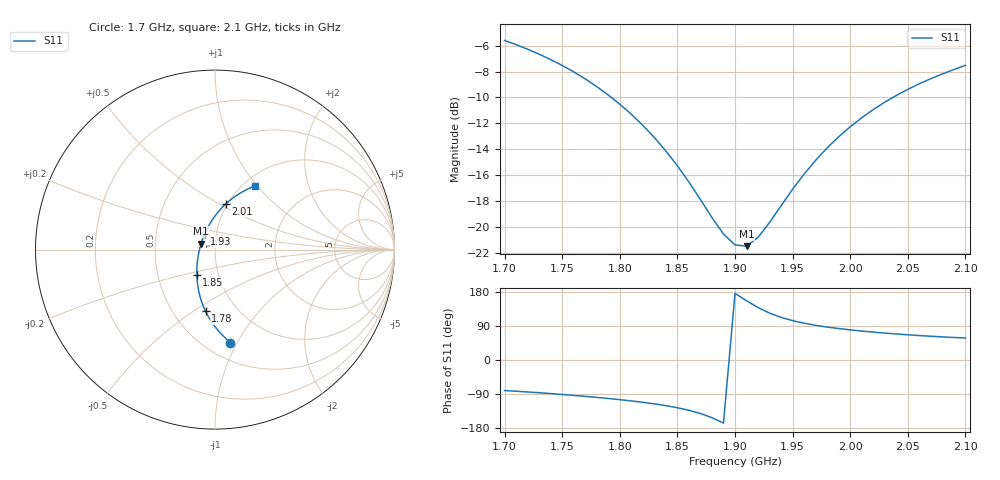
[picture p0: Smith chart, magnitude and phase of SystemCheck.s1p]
! Generated by circuitRF - EM: openEMS
! circuitRF-EM setup: SystemCheck Fine
! circuitRF-EM layout: SystemCheck.c3d
! circuitRF-EM written: 2026-10-19 01:18:16Z
! circuitRF-EM geometry: 3c7697fa9fd6841b
! circuitRF-EM mesh: 0e8366f4b078f3f9
! circuitRF-EM ports: 84820064c771a764
! circuitRF-EM model: openEMS 0.37.0 (v0.37.0, CSXCAD v0.7.0)
! circuitRF-EM port 1: 'port/1' from 'armLo' to 'armHi', lumped, 50 Ohm
! circuitRF-EM 3D grid: 185 x 131 x 174 = 4216890 cells; smallest cell 866.545 um on y, set by 'armLo' edge at y = -1.9 mm; 'armHi' edge at y = -1.9 mm; 'port/1' port extent at y = -1.9 mm; 'armLo' edge at y = 1.9 mm; 'armHi' edge at y = 1.9 mm; 'port/1' port extent at y = 1.9 mm
! circuitRF-EM 3D openEMS run port 1: dt 1.8774E-12 s (estimate 1.82744E-12 s), 7099 steps, port signals unmeasured (stopped within the pulse) and energy 44 dB against 40 dB, stopped by openEMS's energy criterion, converged
! circuitRF-EM 3D dielectric loss fitted at: 1.9 GHz
! circuitRF-EM 3D perfect conductors: armLo, armHi
! circuitRF-EM 3D operating temperature: 20 C
! circuitRF-EM: re-running the EM setup rewrites this file. If circuitRF reports it as stale, the layout's cross-section changed after this file was written.
# GHz S RI R 50
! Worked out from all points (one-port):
!   41 points, 1.7 GHz to 2.1 GHz, reference 50 ohm
!   lowest |S11| = -21.5 dB at 1.91 GHz (marker M1), VSWR 1.18, Z = 42.7 + j2.91 ohm
!   |S11| at or under -10 dB: 1.793 GHz to 2.037 GHz (244.5 MHz wide, 12.8 % of centre)
!   S11 on the Smith chart (normalised r, x): 1.7 GHz: 0.66, -0.94; 1.78 GHz: 0.72, -0.56; 1.85 GHz: 0.79, -0.23; 1.93 GHz: 0.88, +0.15; 2.01 GHz: 0.98, +0.54; 2.1 GHz: 1.13, +0.98
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1.7  0.0854 -0.5177
1.73  0.0289 -0.4635
1.75  -0.00697 -0.4201
1.77  -0.0388 -0.3707
1.78  -0.0526 -0.3441
1.8  -0.0753 -0.288
1.82  -0.091 -0.2293
1.83  -0.0962 -0.1994
1.84  -0.0996 -0.1693
1.85  -0.1012 -0.1393
1.86  -0.1012 -0.1095
1.87  -0.0995 -0.0799
1.88  -0.0961 -0.0507
1.89  -0.0913 -0.0219
1.9  -0.085 0.00625
1.91  -0.0772 0.0338
1.92  -0.0681 0.0605
1.93  -0.0577 0.0865
1.95  -0.0334 0.1357
1.96  -0.0196 0.1587
1.97  -0.00482 0.1807
1.98  0.0109 0.2015
2  0.0444 0.2395
2.01  0.0621 0.2565
2.03  0.0986 0.2866
2.06  0.1537 0.3222
2.08  0.1891 0.3406
2.1  0.2228 0.3566
